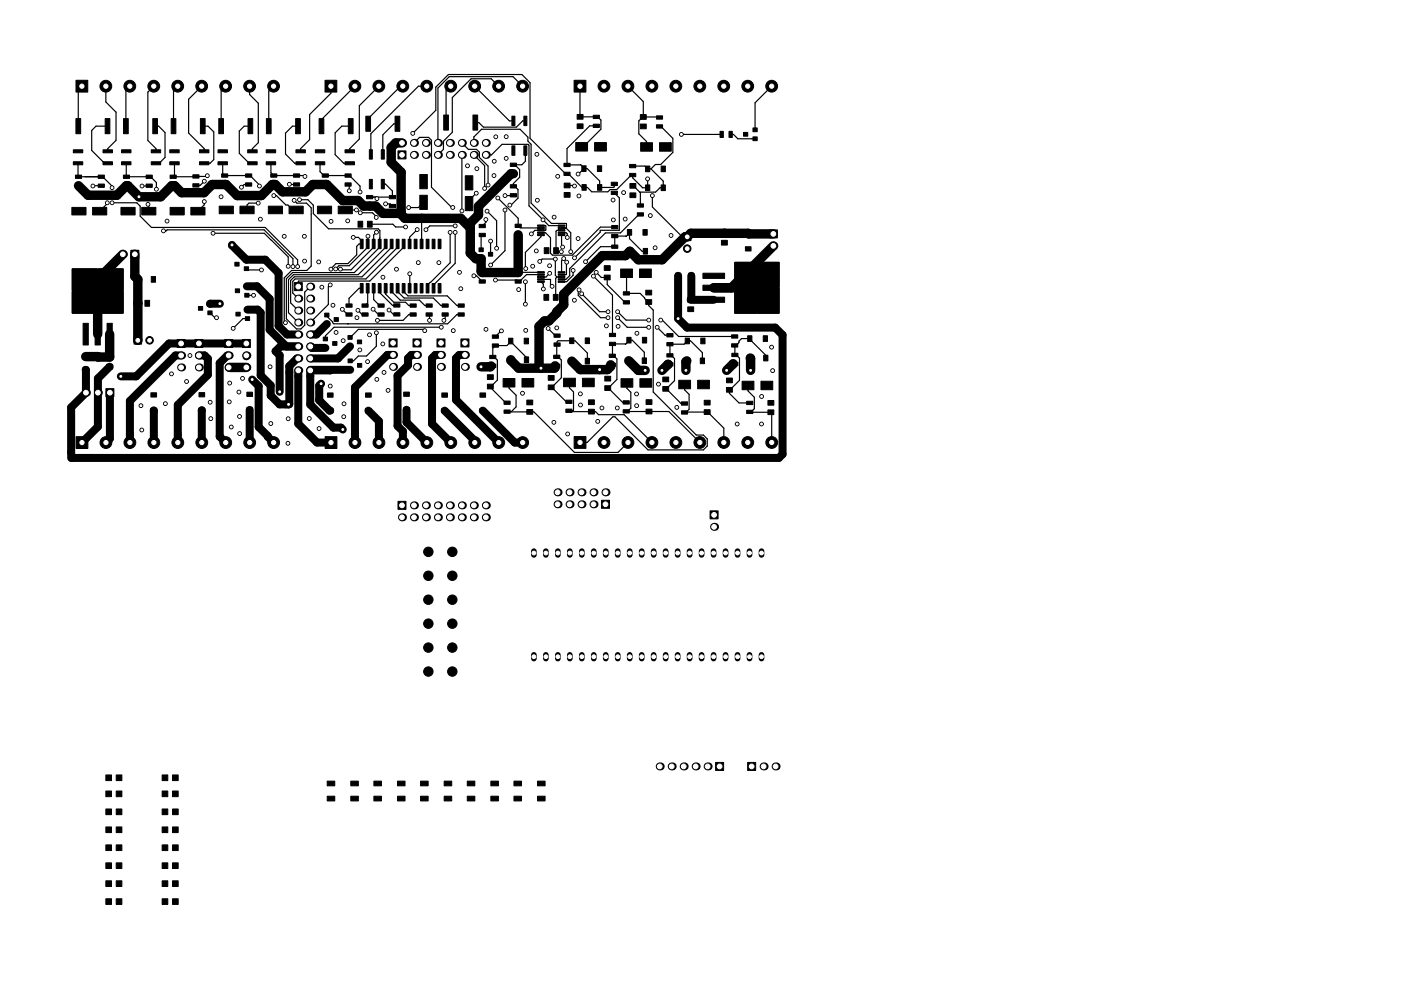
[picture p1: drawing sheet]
<svg xmlns="http://www.w3.org/2000/svg" width="297mm" height="210mm" viewBox="0 0 297 210" stroke-linecap="round" stroke-linejoin="round" font-family="sans-serif">
<g fill="none" stroke="#000" stroke-width="1.2">
<path d="M113.2 116.9v.8M115.7 116.9v.8M118.3 116.9v.8M120.8 116.9v.8M123.4 116.9v.8M125.9 116.9v.8M128.4 116.9v.8M131 116.9v.8M133.5 116.9v.8M136.1 116.9v.8M138.6 116.9v.8M141.1 116.9v.8"/>
<path d="M143.7 116.9v.8M146.2 116.9v.8M148.8 116.9v.8M151.3 116.9v.8M153.8 116.9v.8M156.4 116.9v.8M158.9 116.9v.8M161.5 116.9v.8M113.2 138.9v.8M115.7 138.9v.8M118.3 138.9v.8M120.8 138.9v.8"/>
<path d="M123.4 138.9v.8M125.9 138.9v.8M128.4 138.9v.8M131 138.9v.8M133.5 138.9v.8M136.1 138.9v.8M138.6 138.9v.8M141.1 138.9v.8M143.7 138.9v.8M146.2 138.9v.8M148.8 138.9v.8M151.3 138.9v.8"/>
<path d="M153.8 138.9v.8M156.4 138.9v.8M158.9 138.9v.8M161.5 138.9v.8"/>
</g>
<g fill="#000" stroke="#000" stroke-width=".21">
<path d="M16.1 17h2.5v2.5h-2.5zM68.9 17h2.5v2.5h-2.5zM121.7 17h2.5v2.5h-2.5zM16.1 25.2h1v3.2h-1zM16 37.2h1.3v.7h-1.3zM16 39.1h1.3v.7h-1.3zM15.5 34.3h2v.7h-2zM15.5 31.8h2v.6h-2zM20.8 39.1h1.3v.7h-1.3zM20.8 37.2h1.3v.7h-1.3zM22.3 25.2h1v3.2h-1zM21.8 31.8h2v.6h-2z"/>
<path d="M21.8 34.3h2v.7h-2zM26.2 25.2h1v3.2h-1zM26.2 39.1h1.3v.7h-1.3zM26.2 37.2h1.3v.7h-1.3zM25.8 34.3h2v.7h-2zM25.8 31.8h2v.6h-2zM31 37.2h1.3v.7h-1.3zM31 39.1h1.3v.7h-1.3zM32.4 25.2h1v3.2h-1zM32.1 31.8h2v.6h-2zM32.1 34.3h2v.7h-2zM36.3 25.2h1v3.2h-1z"/>
<path d="M36.1 39.1h1.3v.7h-1.3zM36.1 37.2h1.3v.7h-1.3zM36 31.8h2v.6h-2zM36 34.3h2v.7h-2zM40.9 39h1.3v.7h-1.3zM40.9 37.1h1.3v.7h-1.3zM42.5 25.2h1v3.2h-1zM42.3 34.3h2v.7h-2zM42.3 31.8h2v.6h-2zM46.4 25.2h1v3.2h-1zM46.2 31.8h2v.6h-2zM46.2 34.3h2v.7h-2z"/>
<path d="M47 38.8h1.3v.7h-1.3zM47 36.9h1.3v.7h-1.3zM52.1 36.9h1.3v.7h-1.3zM52.1 38.8h1.3v.7h-1.3zM52.6 25.2h1v3.2h-1zM52.5 34.3h2v.7h-2zM52.5 31.8h2v.6h-2zM56.5 25.2h1v3.2h-1zM56.4 31.8h2v.6h-2zM56.4 34.3h2v.7h-2zM57.4 36.9h1.3v.7h-1.3zM57.4 38.8h1.3v.7h-1.3z"/>
<path d="M62.2 38.8h1.3v.7h-1.3zM62.2 36.9h1.3v.7h-1.3zM62.7 25.2h1v3.2h-1zM62.7 34.3h2v.7h-2zM62.7 31.8h2v.6h-2zM67.7 25.2h1v3.2h-1zM66.9 34.3h2v.7h-2zM66.9 31.8h2v.6h-2zM68.3 38.8h1.3v.7h-1.3zM68.3 36.9h1.3v.7h-1.3zM73.1 36.9h1.3v.7h-1.3zM73.1 38.8h1.3v.7h-1.3z"/>
<path d="M73.9 25.2h1v3.2h-1zM73.2 31.8h2v.6h-2zM73.2 34.3h2v.7h-2zM78.3 38.1h.6v2h-.6zM78.3 31.8h.6v2h-.6zM77.6 24.7h1v3.2h-1zM80.8 38.1h.7v2h-.7zM80.8 31.8h.7v2h-.7zM83.8 24.7h1v3.2h-1zM84.4 32h1.7v1.7h-1.7zM89 37h1.6v3h-1.6zM94.1 24.4h1v3.2h-1z"/>
<path d="M98.7 37.3h1.6v3h-1.6zM100.3 24.4h1v3.2h-1zM108.2 39.2h1.3v.7h-1.3zM108.5 24.6h.7v2h-.7zM108.5 30.9h.7v2h-.7zM108.2 34.6h1.3v.7h-1.3zM108.2 36.5h1.3v.7h-1.3zM111.1 24.6h.6v2h-.6zM111.1 30.9h.6v2h-.6zM119.6 38.8h1.3v1h-1.3zM119.6 36.5h1.3v.7h-1.3zM119.6 34.6h1.3v.7h-1.3z"/>
<path d="M122.1 30.2h2.5v1.8h-2.5zM123.4 35.2h.9v1.2h-.9zM122.4 26.3h1.2v1h-1.2zM122.4 24.3h1.2v1h-1.2zM125.8 24.4h1.3v.7h-1.3zM125.8 26.3h1.3v.7h-1.3zM126.1 30.2h2.5v1.8h-2.5zM126.7 35.2h.9v1.2h-.9zM129.6 38.7h1.3v.7h-1.3zM133.6 38.9h1.2v1h-1.2zM133.5 34.9h1.3v.7h-1.3zM133.5 36.8h1.3v.7h-1.3z"/>
<path d="M135.8 30.3h2.5v1.8h-2.5zM136.9 35.2h.9v1.2h-.9zM135.8 24.3h1.2v1h-1.2zM135.8 26.3h1.2v1h-1.2zM139.2 26.5h1.3v.7h-1.3zM139.2 24.6h1.3v.7h-1.3zM139.8 30.3h2.5v1.8h-2.5zM140.2 35.2h.9v1.2h-.9zM152.7 27.9h.7v1.3h-.7zM154.6 27.9h.7v1.3h-.7zM157.6 28.1h.9v.8h-.9zM159.6 29h.9v.8h-.9z"/>
<path d="M159.6 27.1h.9v.8h-.9zM15.2 44h3v1.6h-3zM19.6 44h3v1.6h-3zM25.6 44h3v1.6h-3zM27.7 53.1h1.7v1.7h-1.7zM28.8 58.7h.9v1.2h-.9zM30 44h3v1.6h-3zM32.1 58.7h.9v1.2h-.9zM36.1 44h3v1.6h-3zM40.5 44h3v1.6h-3zM46.5 43.7h3v1.6h-3zM49.8 55.7h.9v.8h-.9z"/>
<path d="M50.9 43.7h3v1.6h-3zM51.8 56.6h.9v.8h-.9zM51.8 54.7h.9v.8h-.9zM56.9 43.7h3v1.6h-3zM61.3 43.7h3v1.6h-3zM67.3 43.7h3v1.6h-3zM71.7 43.7h3v1.6h-3zM75.9 46.9h1v1.3h-1zM76.4 50.8h.6v2h-.6zM77.7 50.8h.6v2h-.6zM77.9 46.9h1v1.3h-1zM77.7 41.5h1.3v.7h-1.3z"/>
<path d="M77.7 43.4h1.3v.7h-1.3zM78.9 50.8h.6v2h-.6zM80.2 50.8h.6v2h-.6zM81.5 50.8h.6v2h-.6zM82.5 43.4h1.3v.7h-1.3zM82.5 41.5h1.3v.7h-1.3zM82.7 50.8h.6v2h-.6zM84 50.8h.6v2h-.6zM85.3 50.8h.6v2h-.6zM86.5 50.8h.6v2h-.6zM87.8 50.8h.6v2h-.6zM89 41.4h1.6v3h-1.6z"/>
<path d="M89.1 50.8h.6v2h-.6zM90.4 50.8h.6v2h-.6zM91.6 50.8h.6v2h-.6zM92.9 50.8h.6v2h-.6zM98.7 41.7h1.6v3h-1.6zM101.6 54.5h.9v.8h-.9zM101.6 52.6h.9v.8h-.9zM101.6 59.4h1.3v.7h-1.3zM101.6 57.5h1.3v.7h-1.3zM101.6 49.5h1.3v.7h-1.3zM101.6 47.6h1.3v.7h-1.3zM103.6 53.5h.9v.8h-.9z"/>
<path d="M108.2 41.1h1.3v.7h-1.3zM109.2 57.5h1.3v.7h-1.3zM109.2 59.4h1.3v.7h-1.3zM109.2 47.6h1.3v.7h-1.3zM109.2 49.5h1.3v.7h-1.3zM114 49.7h1.4v.3h-1.4zM114 49.2h1.4v.3h-1.4zM114 48.7h1.4v.3h-1.4zM114 48.2h1.4v.3h-1.4zM114 47.7h1.4v.3h-1.4zM114 57.6h1.4v.3h-1.4zM114 58.1h1.4v.3h-1.4z"/>
<path d="M114 58.6h1.4v.3h-1.4zM114 59.1h1.4v.3h-1.4zM114 59.6h1.4v.3h-1.4zM115.4 52.6h1v1.2h-1zM118.4 47.7h1.4v.3h-1.4zM118.4 48.2h1.4v.3h-1.4zM118.4 48.7h1.4v.3h-1.4zM118.4 49.2h1.4v.3h-1.4zM118.4 49.7h1.4v.3h-1.4zM118.4 59.6h1.4v.3h-1.4zM118.4 59.1h1.4v.3h-1.4zM118.4 58.6h1.4v.3h-1.4z"/>
<path d="M118.4 58.1h1.4v.3h-1.4zM118.4 57.6h1.4v.3h-1.4zM117.4 52.6h1v1.2h-1zM119.6 40.8h1.3v1h-1.3zM123.4 39.2h.9v1.2h-.9zM126.7 39.2h.9v1.2h-.9zM128.1 58.4h1.3v1h-1.3zM128.1 56.4h1.3v1h-1.3zM129.6 40.6h1.3v.7h-1.3zM129.7 47.8h1.3v.7h-1.3zM129.7 49.7h1.3v.7h-1.3zM129.7 53.9h1.3v.7h-1.3z"/>
<path d="M129.7 52h1.3v.7h-1.3zM131.6 57.1h2.5v1.8h-2.5zM133 48.7h.9v1.2h-.9zM133.1 52.7h.9v1.2h-.9zM133.6 40.9h1.2v1h-1.2zM135.1 43.2h1.3v.7h-1.3zM135.1 45.1h1.3v.7h-1.3zM135.6 57.1h2.5v1.8h-2.5zM136.3 48.7h.9v1.2h-.9zM136.4 52.7h.9v1.2h-.9zM136.9 39.2h.9v1.2h-.9zM140.2 39.2h.9v1.2h-.9z"/>
<path d="M143.2 58h1.1v1.1h-1.1zM144.9 49.4h1.6v1.6h-1.6zM146 58h1.1v1.1h-1.1zM149 58h4.6v1.1h-4.6zM153 49h1.2v1h-1.2zM153 51h1.2v1h-1.2zM158 49.1h1.2v.9h-1.2zM158 52.4h1.2v.9h-1.2zM163.1 48.8h1.7v1.7h-1.7zM17.6 77.9h1.1v1.1h-1.1zM17.6 75.1h1.1v1.1h-1.1zM17.6 68.6h1.1v4.6h-1.1z"/>
<path d="M15.3 57h5.3v4.6h-5.3zM15.3 61.9h5.3v4.5h-5.3zM20.2 68.6h1.1v4.6h-1.1zM22.6 77.3h1.3v1h-1.3zM22.6 75.3h1.3v1h-1.3zM22.7 68.6h1.1v4.6h-1.1zM20.9 61.9h5.2v4.5h-5.2zM20.9 57h5.2v4.6h-5.2zM15.3 57h10.8v9.4h-10.8zM28.4 71.4h1.6v1.6h-1.6zM28.7 63.7h1v1.3h-1zM30.7 63.7h1v1.3h-1z"/>
<path d="M37.5 72h1.7v1.7h-1.7zM41.3 72h1.7v1.7h-1.7zM42.1 65h.9v.8h-.9zM44.1 66h.9v.8h-.9zM44.1 64.1h.9v.8h-.9zM47.6 72h1.7v1.7h-1.7zM49.9 61.3h.9v.8h-.9zM50 66.2h.9v.8h-.9zM51.4 72h1.7v1.7h-1.7zM51.9 62.2h.9v.8h-.9zM51.9 60.3h.9v.8h-.9zM52 65.3h.9v.8h-.9z"/>
<path d="M52 67.2h.9v.8h-.9zM62.4 60h1.7v1.7h-1.7zM68.5 71.5h.9v.8h-.9zM68.5 73.4h.9v.8h-.9zM68.8 66.4h.9v.8h-.9zM68.8 68.3h.9v.8h-.9zM70.5 72.5h.9v.8h-.9zM70.8 67.4h.9v.8h-.9zM73.8 73.1h.9v.8h-.9zM73.8 71.2h.9v.8h-.9zM73.8 78.1h.9v.8h-.9zM73.8 76.2h.9v.8h-.9z"/>
<path d="M73.4 64.5h1.3v.7h-1.3zM73.4 66.4h1.3v.7h-1.3zM75.8 72.1h.9v.8h-.9zM75.8 77.1h.9v.8h-.9zM76.4 60.2h.6v2h-.6zM76.7 64.5h1.3v.7h-1.3zM76.7 66.4h1.3v.7h-1.3zM77.7 60.2h.6v2h-.6zM78.9 60.2h.6v2h-.6zM80.2 60.2h.6v2h-.6zM80.1 66.4h1.3v.7h-1.3zM80.1 64.5h1.3v.7h-1.3z"/>
<path d="M81.5 60.2h.6v2h-.6zM82.5 71.9h1.7v1.7h-1.7zM82.7 60.2h.6v2h-.6zM84 60.2h.6v2h-.6zM83.5 66.4h1.3v.7h-1.3zM83.5 64.5h1.3v.7h-1.3zM85.3 60.2h.6v2h-.6zM86.5 60.2h.6v2h-.6zM87.6 71.9h1.7v1.7h-1.7zM86.9 66.4h1.3v.7h-1.3zM86.9 64.5h1.3v.7h-1.3zM87.8 60.2h.6v2h-.6z"/>
<path d="M89.1 60.2h.6v2h-.6zM90.4 60.2h.6v2h-.6zM90.3 64.5h1.3v.7h-1.3zM90.3 66.4h1.3v.7h-1.3zM91.6 60.2h.6v2h-.6zM92.6 71.9h1.7v1.7h-1.7zM92.9 60.2h.6v2h-.6zM93.7 66.4h1.3v.7h-1.3zM93.7 64.5h1.3v.7h-1.3zM97.7 71.9h1.7v1.7h-1.7zM97.1 64.5h1.3v.7h-1.3zM97.1 66.4h1.3v.7h-1.3z"/>
<path d="M103.8 75.4h1.3v.7h-1.3zM103.8 77.3h1.3v.7h-1.3zM104.4 73h1.3v.7h-1.3zM104.4 71.1h1.3v.7h-1.3zM107.8 71.8h.9v1.2h-.9zM107.9 75.7h.9v1.2h-.9zM111.1 71.8h.9v1.2h-.9zM111.2 75.7h.9v1.2h-.9zM115.3 62.5h1v1.2h-1zM117.3 62.5h1v1.2h-1zM117.4 77.3h1.3v.7h-1.3zM117.4 75.4h1.3v.7h-1.3z"/>
<path d="M117.5 70.9h1.3v.7h-1.3zM117.5 72.8h1.3v.7h-1.3zM120.8 76h.9v1.2h-.9zM120.8 71.7h.9v1.2h-.9zM124.1 76h.9v1.2h-.9zM124.1 71.7h.9v1.2h-.9zM129.2 77h1.3v.7h-1.3zM129.2 75.1h1.3v.7h-1.3zM129.2 72.6h1.3v.7h-1.3zM129.2 70.7h1.3v.7h-1.3zM132.2 63.8h1.3v.7h-1.3zM132.2 61.9h1.3v.7h-1.3z"/>
<path d="M132.9 75.9h.9v1.2h-.9zM132.9 71.6h.9v1.2h-.9zM136.2 75.9h.9v1.2h-.9zM136.2 71.6h.9v1.2h-.9zM136.9 61.6h1.3v1h-1.3zM136.9 63.6h1.3v1h-1.3zM141.4 70.8h1.3v.7h-1.3zM141.4 72.7h1.3v.7h-1.3zM141.4 75h1.3v.7h-1.3zM141.4 76.9h1.3v.7h-1.3zM145.2 76h.9v1.2h-.9zM145.3 71.7h.9v1.2h-.9z"/>
<path d="M145.8 63.1h1.3v1h-1.3zM145.8 65.1h1.3v1h-1.3zM148.5 76h.9v1.2h-.9zM148.6 71.7h.9v1.2h-.9zM149 60.5h4.6v1.1h-4.6zM149 63h4.6v1.1h-4.6zM155.8 55.7h9.4v10.8h-9.4zM155.8 55.7h4.5v5.2h-4.5zM155.8 61.2h4.5v5.3h-4.5zM155.1 71h1.3v.7h-1.3zM155.1 72.9h1.3v.7h-1.3zM155.2 75h1.3v.7h-1.3z"/>
<path d="M155.2 76.9h1.3v.7h-1.3zM158.5 71.2h.9v1.2h-.9zM158.6 75.4h.9v1.2h-.9zM160.6 61.2h4.6v5.3h-4.6zM160.6 55.7h4.6v5.2h-4.6zM161.8 71.2h.9v1.2h-.9zM161.9 75.4h.9v1.2h-.9zM16.1 92.6h2.5v2.5h-2.5zM22.4 82.5h1.7v1.7h-1.7zM32 86.6h1.2v.9h-1.2zM32 83.3h1.2v.9h-1.2zM42.2 83.3h1.2v.9h-1.2z"/>
<path d="M42.2 86.6h1.2v.9h-1.2zM52.3 86.5h1.2v.9h-1.2zM52.3 83.2h1.2v.9h-1.2zM68.9 92.6h2.5v2.5h-2.5zM69.4 83.4h1.2v.9h-1.2zM69.4 86.7h1.2v.9h-1.2zM77.5 83.4h1.2v.9h-1.2zM77.5 86.7h1.2v.9h-1.2zM85.6 86.5h1.2v.9h-1.2zM85.6 83.2h1.2v.9h-1.2zM93.7 83.4h1.2v.9h-1.2zM93.7 86.7h1.2v.9h-1.2z"/>
<path d="M101.8 86.7h1.2v.9h-1.2zM101.8 83.4h1.2v.9h-1.2zM103.3 79.5h1.3v1h-1.3zM103.3 81.5h1.3v1h-1.3zM106.7 80.3h2.5v1.8h-2.5zM106.9 87h1.3v.7h-1.3zM106.9 85.1h1.3v.7h-1.3zM110.7 80.3h2.5v1.8h-2.5zM111.7 84.9h1.2v1h-1.2zM111.7 86.9h1.2v1h-1.2zM116.2 79.7h1.3v1h-1.3zM116.2 81.7h1.3v1h-1.3z"/>
<path d="M119.5 80.2h2.5v1.8h-2.5zM120 86.8h1.3v.7h-1.3zM120 84.9h1.3v.7h-1.3zM121.7 92.6h2.5v2.5h-2.5zM123.5 80.2h2.5v1.8h-2.5zM124.8 86.8h1.2v1h-1.2zM124.8 84.8h1.2v1h-1.2zM128.2 81.8h1.3v1h-1.3zM128.2 79.8h1.3v1h-1.3zM131.7 80.3h2.5v1.8h-2.5zM132.1 86.9h1.3v.7h-1.3zM132.1 85h1.3v.7h-1.3z"/>
<path d="M135.7 80.3h2.5v1.8h-2.5zM137 84.8h1.2v1h-1.2zM137 86.8h1.2v1h-1.2zM140.5 82h1.3v1h-1.3zM140.5 80h1.3v1h-1.3zM143.9 80.7h2.5v1.8h-2.5zM144.5 85.3h1.3v.7h-1.3zM144.5 87.2h1.3v.7h-1.3zM147.9 80.7h2.5v1.8h-2.5zM149.3 84.9h1.3v1h-1.3zM149.3 86.9h1.3v1h-1.3zM154 80.2h1.3v1h-1.3z"/>
<path d="M154 82.2h1.3v1h-1.3zM157.3 80.9h2.5v1.8h-2.5zM158.3 87h1.3v.7h-1.3zM158.3 85.1h1.3v.7h-1.3zM161.3 80.9h2.5v1.8h-2.5zM162.8 87h1.3v1h-1.3zM162.8 85h1.3v1h-1.3zM84.4 106.4h1.7v1.7h-1.7zM127.5 106.1h1.7v1.7h-1.7zM150.6 108.4h1.6v1.7h-1.6zM22.4 179.3h1.2v1.2h-1.2zM22.4 175.4h1.2v1.2h-1.2z"/>
<path d="M22.4 171.6h1.2v1.2h-1.2zM22.4 167.8h1.2v1.2h-1.2zM22.4 164.4h1.2v1.2h-1.2zM24.6 179.3h1.2v1.2h-1.2zM24.6 175.4h1.2v1.2h-1.2zM24.6 171.6h1.2v1.2h-1.2zM24.6 167.8h1.2v1.2h-1.2zM24.6 164.4h1.2v1.2h-1.2zM34.4 179.3h1.2v1.2h-1.2zM34.4 175.4h1.2v1.2h-1.2zM34.4 171.6h1.2v1.2h-1.2zM34.4 167.8h1.2v1.2h-1.2z"/>
<path d="M34.4 164.4h1.2v1.2h-1.2zM36.6 179.3h1.2v1.2h-1.2zM36.6 175.4h1.2v1.2h-1.2zM36.6 171.6h1.2v1.2h-1.2zM36.6 167.8h1.2v1.2h-1.2zM36.6 164.4h1.2v1.2h-1.2zM69.4 168.9h1.6v1h-1.6zM69.4 165.7h1.6v1h-1.6zM74.4 168.9h1.6v1h-1.6zM74.4 165.7h1.6v1h-1.6zM79.3 165.7h1.6v1h-1.6zM79.3 168.9h1.6v1h-1.6z"/>
<path d="M84.3 165.7h1.6v1h-1.6zM84.3 168.9h1.6v1h-1.6zM89.2 165.7h1.6v1h-1.6zM89.2 168.9h1.6v1h-1.6zM94.2 165.7h1.6v1h-1.6zM94.2 168.9h1.6v1h-1.6zM99.1 165.7h1.6v1h-1.6zM99.1 168.9h1.6v1h-1.6zM104.1 165.7h1.6v1h-1.6zM104.1 168.9h1.6v1h-1.6zM109 168.9h1.6v1h-1.6zM109 165.7h1.6v1h-1.6z"/>
<path d="M114 168.9h1.6v1h-1.6zM114 165.7h1.6v1h-1.6zM151.7 161.8h1.7v1.7h-1.7zM158.5 161.8h1.7v1.7h-1.7zM22.4 190.7h1.2v1.2h-1.2zM22.4 183.1h1.2v1.2h-1.2zM22.4 186.9h1.2v1.2h-1.2zM24.6 190.7h1.2v1.2h-1.2zM24.6 183.1h1.2v1.2h-1.2zM24.6 186.9h1.2v1.2h-1.2zM34.4 190.7h1.2v1.2h-1.2zM34.4 183.1h1.2v1.2h-1.2z"/>
<path d="M34.4 186.9h1.2v1.2h-1.2zM36.6 190.7h1.2v1.2h-1.2zM36.6 183.1h1.2v1.2h-1.2zM36.6 186.9h1.2v1.2h-1.2z"/>
<circle cx="22.4" cy="18.3" r="1.25"/>
<circle cx="27.5" cy="18.3" r="1.25"/>
<circle cx="32.6" cy="18.3" r="1.25"/>
<circle cx="37.7" cy="18.3" r="1.25"/>
<circle cx="42.8" cy="18.3" r="1.25"/>
<circle cx="47.8" cy="18.3" r="1.25"/>
<circle cx="52.9" cy="18.3" r="1.25"/>
<circle cx="58" cy="18.3" r="1.25"/>
<circle cx="75.2" cy="18.3" r="1.25"/>
<circle cx="80.3" cy="18.3" r="1.25"/>
<circle cx="85.4" cy="18.3" r="1.25"/>
<circle cx="90.5" cy="18.3" r="1.25"/>
<circle cx="95.6" cy="18.3" r="1.25"/>
<circle cx="100.6" cy="18.3" r="1.25"/>
<circle cx="105.7" cy="18.3" r="1.25"/>
<circle cx="110.8" cy="18.3" r="1.25"/>
<circle cx="128.1" cy="18.3" r="1.25"/>
<circle cx="133.1" cy="18.3" r="1.25"/>
<circle cx="138.2" cy="18.3" r="1.25"/>
<circle cx="143.3" cy="18.3" r="1.25"/>
<circle cx="148.4" cy="18.3" r="1.25"/>
<circle cx="153.5" cy="18.3" r="1.25"/>
<circle cx="158.5" cy="18.3" r="1.25"/>
<circle cx="163.6" cy="18.3" r="1.25"/>
<circle cx="19.7" cy="39.5" r=".4"/>
<circle cx="23.8" cy="39.8" r=".4"/>
<circle cx="30.1" cy="39.5" r=".4"/>
<circle cx="43.3" cy="38.5" r=".4"/>
<circle cx="44" cy="37.3" r=".4"/>
<circle cx="51.2" cy="39.7" r=".4"/>
<circle cx="55" cy="39.5" r=".4"/>
<circle cx="61.4" cy="39.1" r=".4"/>
<circle cx="64.7" cy="37.4" r=".4"/>
<circle cx="87.5" cy="28.3" r=".4"/>
<circle cx="99.1" cy="35.2" r=".4"/>
<circle cx="101.1" cy="35.8" r=".4"/>
<circle cx="102.8" cy="40" r=".4"/>
<circle cx="103.5" cy="39.3" r=".4"/>
<circle cx="104.7" cy="37.3" r=".4"/>
<circle cx="104.8" cy="34.2" r=".4"/>
<circle cx="105.1" cy="29" r=".4"/>
<circle cx="107.3" cy="33.6" r=".4"/>
<circle cx="107.3" cy="29" r=".4"/>
<circle cx="113.8" cy="32.7" r=".4"/>
<circle cx="118.2" cy="37.4" r=".4"/>
<circle cx="121.8" cy="39.5" r=".4"/>
<circle cx="122.6" cy="36.9" r=".4"/>
<circle cx="137.3" cy="37.9" r=".4"/>
<circle cx="144.5" cy="28.5" r=".4"/>
<circle cx="22.7" cy="43" r=".4"/>
<circle cx="23.8" cy="43" r=".4"/>
<circle cx="29.5" cy="41.8" r=".4"/>
<circle cx="31.4" cy="43.4" r=".4"/>
<circle cx="33.2" cy="40.2" r=".4"/>
<circle cx="34.7" cy="49" r=".4"/>
<circle cx="35.4" cy="46.9" r=".4"/>
<circle cx="43.3" cy="42.8" r=".4"/>
<circle cx="45.2" cy="49.5" r=".4"/>
<circle cx="46.9" cy="41.8" r=".4"/>
<circle cx="49.2" cy="52" r=".4"/>
<circle cx="54.7" cy="43.1" r=".4"/>
<circle cx="55.2" cy="46.5" r=".4"/>
<circle cx="55.4" cy="57.3" r=".4"/>
<circle cx="58.1" cy="41.5" r=".4"/>
<circle cx="60.3" cy="50.1" r=".4"/>
<circle cx="61.1" cy="56.5" r=".4"/>
<circle cx="62.1" cy="56.6" r=".4"/>
<circle cx="62.4" cy="42.5" r=".4"/>
<circle cx="63.1" cy="56.6" r=".4"/>
<circle cx="63.5" cy="42.4" r=".4"/>
<circle cx="64.5" cy="50.1" r=".4"/>
<circle cx="64.6" cy="55.4" r=".4"/>
<circle cx="67.6" cy="55.6" r=".4"/>
<circle cx="70.2" cy="57.1" r=".4"/>
<circle cx="70.2" cy="47" r=".4"/>
<circle cx="71.2" cy="57.1" r=".4"/>
<circle cx="72.2" cy="57.1" r=".4"/>
<circle cx="73.7" cy="46.9" r=".4"/>
<circle cx="74.1" cy="40.5" r=".4"/>
<circle cx="74.9" cy="50.4" r=".4"/>
<circle cx="75.6" cy="44.5" r=".4"/>
<circle cx="76.3" cy="40.7" r=".4"/>
<circle cx="76.4" cy="45.1" r=".4"/>
<circle cx="78" cy="50.1" r=".4"/>
<circle cx="79.8" cy="46.1" r=".4"/>
<circle cx="79.8" cy="49.3" r=".4"/>
<circle cx="79.9" cy="42.1" r=".4"/>
<circle cx="81.2" cy="58.8" r=".4"/>
<circle cx="81.7" cy="43.3" r=".4"/>
<circle cx="84.1" cy="57.1" r=".4"/>
<circle cx="86" cy="48.2" r=".4"/>
<circle cx="86.6" cy="44" r=".4"/>
<circle cx="86.9" cy="58.1" r=".4"/>
<circle cx="88.5" cy="48.7" r=".4"/>
<circle cx="88.7" cy="55.7" r=".4"/>
<circle cx="90.3" cy="48.7" r=".4"/>
<circle cx="93.1" cy="55.7" r=".4"/>
<circle cx="95.4" cy="49.3" r=".4"/>
<circle cx="96" cy="44" r=".4"/>
<circle cx="96.5" cy="49.3" r=".4"/>
<circle cx="96.5" cy="47.9" r=".4"/>
<circle cx="97.4" cy="57.8" r=".4"/>
<circle cx="97.9" cy="44.7" r=".4"/>
<circle cx="100.5" cy="58.5" r=".4"/>
<circle cx="101" cy="41" r=".4"/>
<circle cx="103" cy="46.6" r=".4"/>
<circle cx="103.3" cy="44.8" r=".4"/>
<circle cx="104" cy="51.2" r=".4"/>
<circle cx="104" cy="56.2" r=".4"/>
<circle cx="105" cy="59.4" r=".4"/>
<circle cx="105.3" cy="52.7" r=".4"/>
<circle cx="105.5" cy="42" r=".4"/>
<circle cx="107.1" cy="44.6" r=".4"/>
<circle cx="107.1" cy="41.5" r=".4"/>
<circle cx="108.1" cy="43.5" r=".4"/>
<circle cx="111.4" cy="59.8" r=".4"/>
<circle cx="111.5" cy="57" r=".4"/>
<circle cx="112.7" cy="49.6" r=".4"/>
<circle cx="112.9" cy="56.5" r=".4"/>
<circle cx="113.7" cy="53.2" r=".4"/>
<circle cx="113.9" cy="42.5" r=".4"/>
<circle cx="114.4" cy="55.5" r=".4"/>
<circle cx="115.1" cy="46.6" r=".4"/>
<circle cx="116.5" cy="56.4" r=".4"/>
<circle cx="116.5" cy="58" r=".4"/>
<circle cx="117.5" cy="46.1" r=".4"/>
<circle cx="117.7" cy="55" r=".4"/>
<circle cx="119" cy="53.4" r=".4"/>
<circle cx="119.3" cy="52.4" r=".4"/>
<circle cx="119.5" cy="54.9" r=".4"/>
<circle cx="120.2" cy="55.6" r=".4"/>
<circle cx="120.3" cy="50.4" r=".4"/>
<circle cx="121" cy="53.4" r=".4"/>
<circle cx="121.5" cy="57.4" r=".4"/>
<circle cx="121.8" cy="54.7" r=".4"/>
<circle cx="122.6" cy="50.6" r=".4"/>
<circle cx="122.7" cy="41.6" r=".4"/>
<circle cx="124.1" cy="55.5" r=".4"/>
<circle cx="125.8" cy="58.6" r=".4"/>
<circle cx="126.4" cy="57.8" r=".4"/>
<circle cx="130" cy="42.4" r=".4"/>
<circle cx="130" cy="46.7" r=".4"/>
<circle cx="132.2" cy="40.9" r=".4"/>
<circle cx="132.5" cy="46.5" r=".4"/>
<circle cx="137.9" cy="45.7" r=".4"/>
<circle cx="138.3" cy="41.5" r=".4"/>
<circle cx="138.9" cy="52.6" r=".4"/>
<circle cx="142.3" cy="50" r=".4"/>
<circle cx="145.7" cy="52.7" r=".8"/>
<circle cx="25.6" cy="79.9" r=".4"/>
<circle cx="31.7" cy="72.2" r=".8"/>
<circle cx="36.4" cy="79.3" r=".4"/>
<circle cx="40.3" cy="75.4" r=".4"/>
<circle cx="45.9" cy="67.4" r=".4"/>
<circle cx="46.6" cy="64.4" r=".4"/>
<circle cx="49.4" cy="69.7" r=".4"/>
<circle cx="53.8" cy="62.7" r=".4"/>
<circle cx="57.3" cy="77.8" r=".4"/>
<circle cx="60.5" cy="68.5" r=".4"/>
<circle cx="68.2" cy="60.9" r=".4"/>
<circle cx="70" cy="60.4" r=".4"/>
<circle cx="70.6" cy="64.8" r=".4"/>
<circle cx="71.3" cy="70.5" r=".4"/>
<circle cx="72.6" cy="65.6" r=".4"/>
<circle cx="72.8" cy="72.3" r=".4"/>
<circle cx="75.7" cy="67.4" r=".4"/>
<circle cx="75.9" cy="65.8" r=".4"/>
<circle cx="76.3" cy="74.2" r=".4"/>
<circle cx="77.9" cy="76.7" r=".4"/>
<circle cx="78.3" cy="71" r=".4"/>
<circle cx="79.1" cy="65.6" r=".4"/>
<circle cx="79.8" cy="70.6" r=".4"/>
<circle cx="80" cy="68" r=".4"/>
<circle cx="81.2" cy="73" r=".4"/>
<circle cx="81.4" cy="79" r=".4"/>
<circle cx="82.5" cy="65.8" r=".4"/>
<circle cx="90.1" cy="70.2" r=".4"/>
<circle cx="91.1" cy="68" r=".4"/>
<circle cx="93.6" cy="69.4" r=".4"/>
<circle cx="94.1" cy="68" r=".4"/>
<circle cx="96.1" cy="70.1" r=".4"/>
<circle cx="97.7" cy="61.3" r=".4"/>
<circle cx="102" cy="77.8" r=".4"/>
<circle cx="103" cy="69.9" r=".4"/>
<circle cx="106.3" cy="70.2" r=".4"/>
<circle cx="110" cy="61.4" r=".4"/>
<circle cx="111.4" cy="64.5" r=".4"/>
<circle cx="111.5" cy="70.1" r=".4"/>
<circle cx="114.7" cy="78.1" r=".4"/>
<circle cx="115.2" cy="61.3" r=".4"/>
<circle cx="116.2" cy="69.7" r=".4"/>
<circle cx="117.1" cy="60.8" r=".4"/>
<circle cx="118" cy="69.6" r=".4"/>
<circle cx="121.8" cy="63.7" r=".4"/>
<circle cx="122.8" cy="61.5" r=".4"/>
<circle cx="123.3" cy="62.3" r=".4"/>
<circle cx="127.1" cy="78.4" r=".4"/>
<circle cx="128.6" cy="69.1" r=".4"/>
<circle cx="128.9" cy="67.4" r=".4"/>
<circle cx="128.9" cy="66.1" r=".4"/>
<circle cx="130.9" cy="66.1" r=".4"/>
<circle cx="130.9" cy="67.4" r=".4"/>
<circle cx="131" cy="69.2" r=".4"/>
<circle cx="135" cy="70.7" r=".4"/>
<circle cx="136.8" cy="78.6" r=".4"/>
<circle cx="137.6" cy="69.4" r=".4"/>
<circle cx="137.6" cy="67.9" r=".4"/>
<circle cx="139.3" cy="69.4" r=".4"/>
<circle cx="140.1" cy="67.9" r=".4"/>
<circle cx="140.3" cy="78.6" r=".4"/>
<circle cx="143.8" cy="67.6" r=".4"/>
<circle cx="145.4" cy="78.6" r=".4"/>
<circle cx="154.1" cy="78.6" r=".4"/>
<circle cx="159.1" cy="78.6" r=".4"/>
<circle cx="163.6" cy="73.7" r=".4"/>
<circle cx="163.8" cy="78.6" r=".4"/>
<circle cx="22.5" cy="93.9" r="1.25"/>
<circle cx="27.5" cy="93.9" r="1.25"/>
<circle cx="29.9" cy="86.1" r=".4"/>
<circle cx="30.1" cy="91.2" r=".4"/>
<circle cx="32.6" cy="93.9" r="1.25"/>
<circle cx="35.1" cy="85.6" r=".4"/>
<circle cx="37.7" cy="93.9" r="1.25"/>
<circle cx="39.6" cy="80.9" r=".4"/>
<circle cx="42.8" cy="93.9" r="1.25"/>
<circle cx="44.6" cy="85.3" r=".4"/>
<circle cx="44.7" cy="88.8" r=".4"/>
<circle cx="47.9" cy="93.9" r="1.25"/>
<circle cx="48.6" cy="85.3" r=".4"/>
<circle cx="48.7" cy="81.3" r=".4"/>
<circle cx="49" cy="90.6" r=".4"/>
<circle cx="50.7" cy="83.2" r=".4"/>
<circle cx="50.8" cy="88.4" r=".4"/>
<circle cx="50.8" cy="92" r=".4"/>
<circle cx="51.4" cy="80.3" r=".4"/>
<circle cx="52.9" cy="93.9" r="1.25"/>
<circle cx="53.5" cy="80.5" r=".4"/>
<circle cx="57.4" cy="89.9" r=".4"/>
<circle cx="58" cy="93.9" r="1.25"/>
<circle cx="59.3" cy="83.1" r=".4"/>
<circle cx="61" cy="94.1" r=".4"/>
<circle cx="61.1" cy="88.8" r=".4"/>
<circle cx="61.2" cy="85.8" r=".4"/>
<circle cx="65.6" cy="88.8" r=".4"/>
<circle cx="67.7" cy="90.9" r=".4"/>
<circle cx="68.1" cy="81.4" r=".4"/>
<circle cx="70" cy="81.9" r=".4"/>
<circle cx="72.7" cy="91.1" r=".4"/>
<circle cx="72.9" cy="88.4" r=".4"/>
<circle cx="72.9" cy="85.7" r=".4"/>
<circle cx="75.3" cy="93.9" r="1.25"/>
<circle cx="79.9" cy="80.5" r=".4"/>
<circle cx="80.3" cy="93.9" r="1.25"/>
<circle cx="82.3" cy="82.8" r=".4"/>
<circle cx="85.4" cy="93.9" r="1.25"/>
<circle cx="90.5" cy="93.9" r="1.25"/>
<circle cx="95.6" cy="93.9" r="1.25"/>
<circle cx="100.7" cy="93.9" r="1.25"/>
<circle cx="105.7" cy="93.9" r="1.25"/>
<circle cx="110.8" cy="83.4" r=".4"/>
<circle cx="110.8" cy="93.9" r="1.25"/>
<circle cx="117.4" cy="89.6" r=".4"/>
<circle cx="120.4" cy="92.1" r=".4"/>
<circle cx="123" cy="83.6" r=".4"/>
<circle cx="123.1" cy="85.9" r=".4"/>
<circle cx="126.7" cy="89.4" r=".4"/>
<circle cx="127.6" cy="86.6" r=".4"/>
<circle cx="128.1" cy="93.9" r="1.25"/>
<circle cx="130.9" cy="86.6" r=".4"/>
<circle cx="133.1" cy="93.9" r="1.25"/>
<circle cx="135" cy="83.6" r=".4"/>
<circle cx="135" cy="86.1" r=".4"/>
<circle cx="138.2" cy="93.9" r="1.25"/>
<circle cx="139.6" cy="81.5" r=".4"/>
<circle cx="143.3" cy="93.9" r="1.25"/>
<circle cx="143.5" cy="86.4" r=".4"/>
<circle cx="148.4" cy="93.9" r="1.25"/>
<circle cx="153.5" cy="93.9" r="1.25"/>
<circle cx="156.3" cy="90" r=".4"/>
<circle cx="158.5" cy="93.9" r="1.25"/>
<circle cx="161.5" cy="90" r=".4"/>
<circle cx="161.5" cy="84.1" r=".4"/>
<circle cx="163.6" cy="93.9" r="1.25"/>
<circle cx="90.8" cy="117.1" r="1"/>
<circle cx="95.9" cy="117.1" r="1"/>
<circle cx="90.8" cy="132.3" r="1"/>
<circle cx="90.8" cy="137.4" r="1"/>
<circle cx="90.8" cy="127.2" r="1"/>
<circle cx="90.8" cy="122.2" r="1"/>
<circle cx="95.9" cy="132.3" r="1"/>
<circle cx="95.9" cy="137.4" r="1"/>
<circle cx="95.9" cy="127.2" r="1"/>
<circle cx="95.9" cy="122.2" r="1"/>
<circle cx="90.8" cy="142.5" r="1"/>
<circle cx="95.9" cy="142.5" r="1"/>
</g>
<g fill="#000">
<circle cx="85.2" cy="30.3" r=".85"/>
<circle cx="87.8" cy="30.3" r=".85"/>
<circle cx="87.8" cy="32.9" r=".85"/>
<circle cx="90.3" cy="30.3" r=".85"/>
<circle cx="90.3" cy="32.9" r=".85"/>
<circle cx="92.8" cy="30.3" r=".85"/>
<circle cx="92.8" cy="32.9" r=".85"/>
<circle cx="95.4" cy="32.9" r=".85"/>
<circle cx="95.4" cy="30.3" r=".85"/>
<circle cx="97.9" cy="32.9" r=".85"/>
<circle cx="97.9" cy="30.3" r=".85"/>
<circle cx="100.5" cy="32.9" r=".85"/>
<circle cx="100.5" cy="30.3" r=".85"/>
<circle cx="103" cy="30.3" r=".85"/>
<circle cx="103" cy="32.9" r=".85"/>
<circle cx="26" cy="53.9" r=".85"/>
<circle cx="164" cy="52.2" r=".85"/>
<circle cx="38.4" cy="75.4" r=".85"/>
<circle cx="38.4" cy="78" r=".85"/>
<circle cx="42.2" cy="75.4" r=".85"/>
<circle cx="42.2" cy="78" r=".85"/>
<circle cx="48.5" cy="75.4" r=".85"/>
<circle cx="48.5" cy="78" r=".85"/>
<circle cx="52.2" cy="75.4" r=".85"/>
<circle cx="52.2" cy="78" r=".85"/>
<circle cx="63.2" cy="71" r=".85"/>
<circle cx="63.2" cy="65.9" r=".85"/>
<circle cx="63.2" cy="68.4" r=".85"/>
<circle cx="63.2" cy="73.5" r=".85"/>
<circle cx="63.2" cy="78.6" r=".85"/>
<circle cx="63.2" cy="76" r=".85"/>
<circle cx="63.2" cy="63.3" r=".85"/>
<circle cx="65.8" cy="71" r=".85"/>
<circle cx="65.8" cy="73.5" r=".85"/>
<circle cx="65.8" cy="60.8" r=".85"/>
<circle cx="65.8" cy="63.3" r=".85"/>
<circle cx="65.8" cy="68.4" r=".85"/>
<circle cx="65.8" cy="78.6" r=".85"/>
<circle cx="65.8" cy="65.9" r=".85"/>
<circle cx="65.8" cy="76" r=".85"/>
<circle cx="83.3" cy="75.3" r=".85"/>
<circle cx="83.3" cy="77.8" r=".85"/>
<circle cx="88.4" cy="75.3" r=".85"/>
<circle cx="88.4" cy="77.8" r=".85"/>
<circle cx="93.5" cy="77.8" r=".85"/>
<circle cx="93.5" cy="75.3" r=".85"/>
<circle cx="98.6" cy="77.8" r=".85"/>
<circle cx="98.6" cy="75.3" r=".85"/>
<circle cx="18.2" cy="83.3" r=".85"/>
<circle cx="20.8" cy="83.3" r=".85"/>
<circle cx="85.2" cy="109.8" r=".85"/>
<circle cx="87.8" cy="109.8" r=".85"/>
<circle cx="87.8" cy="107.2" r=".85"/>
<circle cx="90.3" cy="109.8" r=".85"/>
<circle cx="90.3" cy="107.2" r=".85"/>
<circle cx="92.8" cy="109.8" r=".85"/>
<circle cx="92.8" cy="107.2" r=".85"/>
<circle cx="95.4" cy="109.8" r=".85"/>
<circle cx="95.4" cy="107.2" r=".85"/>
<circle cx="97.9" cy="109.8" r=".85"/>
<circle cx="97.9" cy="107.2" r=".85"/>
<circle cx="100.5" cy="107.2" r=".85"/>
<circle cx="100.5" cy="109.8" r=".85"/>
<circle cx="103" cy="109.8" r=".85"/>
<circle cx="103" cy="107.2" r=".85"/>
<circle cx="118.2" cy="107" r=".85"/>
<circle cx="118.2" cy="104.5" r=".85"/>
<circle cx="120.8" cy="104.5" r=".85"/>
<circle cx="120.8" cy="107" r=".85"/>
<circle cx="123.3" cy="104.5" r=".85"/>
<circle cx="123.3" cy="107" r=".85"/>
<circle cx="125.8" cy="107" r=".85"/>
<circle cx="125.8" cy="104.5" r=".85"/>
<circle cx="128.4" cy="104.5" r=".85"/>
<circle cx="151.4" cy="111.8" r=".85"/>
<circle cx="139.9" cy="162.6" r=".85"/>
<circle cx="142.4" cy="162.6" r=".85"/>
<circle cx="145" cy="162.6" r=".85"/>
<circle cx="147.5" cy="162.6" r=".85"/>
<circle cx="150" cy="162.6" r=".85"/>
<circle cx="161.9" cy="162.6" r=".85"/>
<circle cx="164.4" cy="162.6" r=".85"/>
</g>
<g fill="none" stroke="#000" stroke-width="2">
<path d="M16.6 39.4l2.1 2h6.1l2-2h.3l2.4 2.4h4.6l2.3-2.4h.6l1.5 1.5h4.7l1.8-1.8h2.9l2.4 2.4h5.1l2.3-2.4h.6l1.6 1.6h4.9l1.5-1.6h3l3.4 3.4h3.2l1.2 1.2h2.5l1.6 1.6h3.6M85.2 30.3h-1.3l-1 1v3.1l2.1 2.1v8.5l-.2 .3M108.8 36.9h-.4l-6.9 6.9v1.8l-1.8 1.7v6.4l1.2 1.2h1.1v2.7l.2 .2h7.7v-8M23.2 59.3l-2.5 2.4M26 53.9l-5.3 5.4v11.6M28.6 53.9v4.7l.6 .7v12.9M84.8 45.3l1.1 1h11.8l2 2.1M153.6 49.5h.1M164 49.6l-17.5-.1-.8 .7h-.5l-4.8 4.9h-5.1l-1.8-1.8-.9 .9h-4.9l-8.2 8.2v2.3l-1.4 1.4v.3l-1.7 1.7h-1l-1.1 1.1v8.5l.4 .4M164 52.2l-8.9 8.9M23.3 70.9v4.9l-5.1-.1M29.2 64.3h.1"/>
<path d="M29.2 72.2h.1M48.6 78h3.6M104.1 77.6l-.2 .2h-1.9M108.3 76.3l1.7 1.8h7.5l.2-.5M121.2 76.6l1.8 1.8h5.8l.7-.7v-.3M133.3 76.5l2.1 2.1h1.4M141.7 77.3l-1.4 1.3M145.6 76.6l-.2 .2v1.8M151.3 61.1h9.2M155.5 77.2l-1.4 1.4M159.1 76v2.6M162.9 63.8l.1 .1"/>
</g>
<g fill="none" stroke="#000" stroke-width=".25">
<path d="M17.4 18.3l-.8 .8v7.7M22.4 18.3v3.3l2.2 2.2v6l-1.8 1.7v.6M27.5 18.3l-.8 .8v7.7M32.6 18.3l-1.3 1.2v10.3l1.8 1.7v.6M37.7 18.3l-.9 .9v7.6M42.8 18.3l-2.8 2.8v7.1l3.3 3.3v.6M47.8 18.3l-.9 .9v7.6M52.9 18.3v1.8l1.9 1.8v8.4l-1.3 1.2v.6M58 18.3l-1 1v7.5M70.2 18.3v1.5l-4.6 4.5v5.3l-1.9 1.9v.6M75.2 18.3l-7 7.1v1.4M80.3 18.3l-4.1 4.1v7.1l-2 2v.6"/>
<path d="M85.4 18.3h-.5l-6.8 6.9v1.1M90.5 18.3h-1.8l-10.1 10.1v4.4M95.6 18.3l-1 1v6.7M100.6 18.3l7.4 7.3h.8M105.7 18.3l-1.6-1.6h-4.2l-4 4v7.4l-1.9 1.8v1.8l-1.2 1.2M110.8 18.3l-2-2h-13.5l-2.5 2.4v11.6M123 18.3v6.5h3.7l.7 .7v1.9l-3.7 3.7h-.4M133.1 18.3l3.3 3.2v3.3M163.6 18.3l-3.5 3.5v5.7M16.5 34.6l.1 2.9h5.2l2 2v.3M21.5 39.4l-1.8 .1M22.8 26.8h-2.4l-1 .9v4.2l2.8 2.7h.6"/>
<path d="M26.8 34.6v2.9h5.1l1.3 1.2v1.5M31.6 39.4l-1.5 .1M32.9 26.8h.7l1.4 1.3v5.3l-1.3 1.2h-.6M37 34.6v2.6l-.3 .3 7.1-.1 .2-.1M43 26.8h1.1l1.2 1.2v5.9l-.8 .7h-1.2M43.3 38.5l-.9 .8h-.9M47.2 34.6v2.2l.4 .4h5.4l2 2v.3M52.7 39.1h-.9l-.6 .6M53.1 26.8h-1.3l-1.1 1v4.7l2.1 2.1h.7M57.4 34.6v2l.6 .6h6.5l.2 .2M61.4 39.1h1.5M63.2 26.8h-1.2l-1.5 1.4v4.5l2 1.9h1.2"/>
<path d="M67.9 34.6v1.8l.8 .8h5.4l2.2 2.3v1.2M73.8 39.1l.3 .3v1.1M74.4 26.8h-1.9l-1.4 1.4v4.6l1.8 1.8h1.3M81.2 39.1h.5l1.5 1.4v1.3h-4.8M84.3 26.3h-.8l-2.3 2.3v4.2M87.5 28.3l4.9-4.9v-4.9l2.7-2.7h15.6l1.7 1.7v11.8l7.5 7.6h.6l2.9 2.9h1.1l1 .9h3.4l.5-.5h1.4l3-3.1h.3v.6l2.1 2.1h1.1v-1.9M87.8 30.3l1.1-1.2h2l.6 .7v9.9l4.3 4.3h.2M97.9 32.9v11.8M97.9 30.3l1.4 1.4h1.7l.6 .6v1.1l1.9 1.8v4.1M100.5 30.3v-1.2l1.6-1.7h8.2l1.6 1.7v.8l.7 .7v12.5l4.3 4.3h3.1v1M100.5 32.9l2.3 2.2v4.9M103 32.9h1.2l2.2-2.3h5.6l.2 .2v12.9l4.2 4.2h2.7"/>
<path d="M109.1 35l1.1 1v1.6l-1.4 1.3v.6h.3l.7 .7v1.8l-1.5 1.5h-.2M111.4 31.9v2.3l-.8 .8h-1.8M111.4 25.6h-.6l-1.3 1.4h-7l-1-1h-.7M120.2 39.3h1.5l.1 .2M123.8 35.8h.7l2.6 2.6v1.4h3l.1-.2v-.6M123.8 35.8l-1.2 1.1M126.4 24.8h.1M126.4 26.7h-1.4l-4.8 4.8v3.5l2.9-.1 .7 .9M134.1 35.2h2.6l.6 .6h.7M134.2 39.4l1.6 1.5v2.7M138 35.8l2.6 2.6v1.4h-.7l-.9 1h-3.4M139.8 26.8h.3l2.6 2.6v2.9l-2.6 2.6h-1.2l-.9 .9"/>
<path d="M139.8 24.9l-.1-.1h-3.4l-.9 .8v2.8l1.7 1.6v1.2M144.5 28.5h8.5M154.9 28.5h.6l.9 .9h3.7M22.7 43v.2l-1.6 1.6h-.7M23.8 43h5.2l.7 .7v2.2l2.4 2.4h24.1l6.9 6.8v1.5M31.4 43.4l.1 .1v1.3M34.7 49h.5l.2-.2h20.6l6.1 6.1v1.7M43.3 42.8v.6l-1.3 1.4M45.2 49.5h10.8l5.1 5v2M52.2 57l.3 .3h2.9M54.7 43.1h-1.9l-.4 .4v1M58 41.5h.6l2 2h.4l1.1 1h.7"/>
<path d="M62.4 42.5l.6 .6h2l1 1v12.4l-.9 .9h-3.3l-1.5 1.6v9.2l.2 .3M63.5 42.4h1.8l1.1 1.1v1.8l3.3 3.2h10.5l.3 .4v3.6l-5.4 5.3h-13.1l-1.3 1.3v8.5l2.2 2.2h.9l.8-.8v-7l1.2-1.2M73.2 44.5h2.4M74.9 50.4h1.1l.7 .7v1.4M76.4 45.1h2.6l.8 .9v.1M76.7 51.8h-.6l-.5 .5v1.8l-1.8 1.8h-2.6l-1 1.2M78 51.1v1.4l-4 3.9h-2.2l-.6 .7M78 50.1v1.7M78.4 47.6h4.9l.6 .6h2.1M79.6 41.8l.3 .3M79.8 49.3l-.6 .6v2.6l-4.8 4.7h-2.1l-.1-.1M81.2 45.3v.8"/>
<path d="M81.7 43.3h1l.5 .4h-.6M81.8 51.8v.7l-5.9 5.8h-13.7l-1 1v7.1l2 2M83 51.8v.7l-6.2 6.2h-14.4l-.8 .8v4.8l1.6 1.6M84.3 51.8v.7l-6.7 6.7h-15l-.5 .5v2.5l1.1 1.1M85.6 51.8v.7l-7.2 7.1h-15.1l-.1 1.2M86.9 58.1l-.1 3.1M88.5 48.7l-1.7 1.6v1.5M89.4 46.3v5.5M89.8 42.9l-1.1 1.1h-2.1M95.4 49.3v6.5l-4.7 4.7v.7M96.5 47.9h-5.4l-.8 .8M96.5 49.3v6.6l-4.6 4.6v.7"/>
<path d="M97.9 44.7h.1M100.5 58.5h.5l1.2 1.2M101 41l-1.5 1.5v.7M101 41h.1M102.2 49.9l-.2 .2v2.9M103 46.6v.6l-.8 .8M103.3 44.8l2 2v5.9M104 51.2v2.7M105.5 42l4.4 4.3v1.6l.4 .5h4.4M107.1 44.6v8.6l-3.1 3M109.1 41.4l-2 .1M111.4 59.8v4.7"/>
<path d="M114.4 55.5l.5-.5h2.8v3.4l.4 .4M114.7 57.8h-4.8M114.7 47.9h.9l.1 .9-2.3 .1-.7 .7M114.7 49.9v.3l-3.3 3.3 .1 3.5M114.7 59.3h2v1.1l.4 .4M114.7 58.3h-3.1l-1.4 1.4h-.3l-.3-.3h-4.6M114.7 59.8l.5 .5v1M116.5 58l-.7 .8h-1.1M118.1 58.8h1M118.1 58.8l-.3 .3v4M119.1 48.9h-1l-.2 .2v4.1l.2 .2h.9M119.1 48.4h.9"/>
<path d="M119.1 49.9v2.3l.2 .2M119.1 49.4h.9l.3 .2v.8M119.5 54.9l-.4 .4v2.5M120 48.4l1 1v4M120.2 55.6l-.1 2.6-1 .1M121.5 57.4v1l-1.4 1.4h-1M125.8 58.6l4.1 4v8.5M126.4 57.8l1.1 1.1h1.2v1.5l3.8 3.7h.3M130.2 40.9l1.1 1.1v6.8l-4 .1v.4l-5.5 5.4M130.3 48.2h-3l-5.9 5.9h-4.3l-.4-.4v-3.3l-1-1h-1M132.8 58v4.2M133.5 49.3v1.3l2.6 2.7h.7"/>
<path d="M133.5 49.4l-.7 .7h-2.5v2.2h-3l-3.2 3.2M135.8 45.5h-.3l-3.9 3.9h-3.2l-7.6 7.6v1.5l-.8 .8h-.9M138.3 41.5v2.4l6.4 6.3h1M44.5 66.4l1.1 1h.3M52.3 62.6l.1 .1M52.4 62.7h1.4M52.5 67.6h-1l-2.1 2.1M70 60.4l-.4 .4v3.8l-3.8 3.8M72.6 65.6l1.1 1.1h.3M75.9 65.8l.9 .9h.6M76.7 61.2h-.6l-2.1 2.1v1.5M78 61.2v3.1l-.6 .5"/>
<path d="M79.1 65.6l1.1 1.1h.6M79.2 61.2v2.4l1.3 1.2h.3M79.8 70.6v2.9l-2.1 2h-1.7l-1 1.1h-.8M80.5 61.2v.9l2.7 2.7h.9M81.8 61.2v1.2l1.7 1.7h2.5l.7 .7h.9M82.5 65.8l.9 .9h.7M83 61.2v.7l1.9 1.8h4l1.2 1.1h.9M84.3 61.2v.7l1.4 1.3h6.2l1.6 1.6h.9M85.6 61.2v.7l.9 .9h8.3l2.1 2h.9M87.6 66.7h-.9l-1.3 1.3h-5.4M90.1 70.2l-.3-.3h-13.8l-1.8 1.7M91 66.7l.1 1.3"/>
<path d="M93.6 69.4h-22.8l-1.8 1.9v.6M94.4 66.7v1l-.3 .3M97.8 66.7h-.9l-2 2h-24.1l-1.5-1.6v-.3M106.3 70.2l-1.3 1.2M108.3 72.5l3.3 3.3v.5M108.3 72.5l-.8 .8h-2.5l-.5 .6v1.8h.3l.7 .7v4.2l-1.5 1.4v.2l3.2 3.2h.3M108.3 72.4v.1M116.2 69.7l1.5 1.5h.4M122.8 61.5l-.2 .2v1l4.7 4.7h1.6M123.3 62.3l3.8 3.8h1.8M124.5 76.6v-1.7l-2.6-2.6h-3.6l-.2 .2-.1 .7v2.5h.3l.7 .7v3.7l-2 2.1M130.9 67.4l2.1 2h4.6"/>
<path d="M130.9 66.1l1.8 1.8h4.9M132.8 62.2h2.9l1.8 1.9v.7l1 1v17.4l9.1 9.1h1.5l.9 .8v1.5l-.9 .9h-11.7l-7-7.1h-.5l-5.4 5.5h-1.5M132.8 62.2h.1M136.6 76.5v-1.8l-2.5-2.5h-.8l-.7 .8h-2.7l-.1 2.5h.3l.7 .7v4.3l-1.8 1.8M139.3 69.4l1.7 1.7h1M140.1 67.9h.3l3.5 3.5h11.9M148.9 76.6v-1.8l-2.5-2.5h-.7l-.7 .7h-3v2.4h.3l.7 .7v4.7l-1.7 1.7M151.3 63.6h.1M162.4 76v-.6l-3.4-3.6h-1.8l-.5 .6v.3l-.6 .6h-.3v2h.3l.7 .7v4.7l-2.2 2v.8l2.1 2h2.3M107.9 81.2v1.2l1.5 1.5v2.4l-1 1h-.9l5.7 .1 8.6 8.6h9.2l2.1-2.1M116.9 82.2h.1M117 82.2l3.1 3h.5"/>
<path d="M120.7 81.1v1.2l.9 .9v3.9h-1l.2 .2h5.5l.6 .7h5.4l5.9 5.9M128.8 82.3h.2M129 82.3l3 3.1h.8M132.8 87.3h9l6.6 6.6M132.8 87.3h.1M132.9 81.2v1.2l.8 .8v3.4l-.6 .7M141.2 82.5h.1M141.3 82.5l3.1 3.1h.7M145.2 81.6v1.1l.9 1v3.1l-.7 .7h-.3l5-.1 3.4 3.4v3.1M158.6 81.8v1.1l1.3 1.4v2.4l-.6 .7h-.3l4.4 .1 .2 .1v6.3"/>
</g>
<g fill="none" stroke="#000" stroke-width="1.7">
<path d="M49.2 52l3 3.1h4l2.9 2.8v11.3l1.8 1.8h2.3M143.8 58.5v9.1l1.9 1.9h18.7l1.5 1.6v25.3l-.8 .8h-150v-10.8l3.1-3.1v-4.8M146.6 58.5v5M23.3 77.8l-2.5 2.5v10.2l-3.4 3.4M38.4 75.4h-1.2l-9.7 9.7v8.8M42.2 75.4h1.2l.7 .7v3.4l-6.4 6.4v8M46.6 64.4l-2.1 .1M48.5 75.4h-.3l-1.6 1.6v15.6l1.3 1.3M52.2 72.9h-16.4l-6.9 7h-3.3M52.2 75.4v.2M52.3 60.7h2.2l2.7 2.7v6.6l3.5 3.5M52.5 65.7h2.1l.7 .6v13.3l2.1 2.2v2.1l1.9 1.9 2-.1v-8l1.7-1.7h.2"/>
<path d="M63.2 73.5h-3.8l-1 1 .9 .9v7.7M63.2 78.6v11.3l4 4h3M65.8 78.6v7.2l4.9 4.9h1.6l.4 .4M65.8 73.5l.3 .3h2.9M69.3 68.7l-2.2 2.3h-1.3M70.1 78.6h-4.3M74.2 73.5l-2.5 2.5h-5.9M74.2 78.5h-8.3l-.1 .1M83.3 75.3h-1.2l-6.8 6.9v11.7M88.4 75.3h-1.2l-.7 .7v1.5l-2.2 2.2v10.7l1.1 1.1v2.4M93.5 75.3h-1.2l-.7 .7v13.9l4 4M98.6 75.3h-1.2l-.7 .7v8.8l9 9.1"/>
<path d="M146.4 63.6h4.9M23.3 83.3v9.8l-.8 .8M32.6 87.1v6.8M42.8 87.1v6.8M42.8 87v.1M52.9 87v6.9M53.5 80.5l1.3 1.4v8.7l3.2 3.3M68.1 81.4l-.4 .4v3.1l2.3 2.2M78.1 87.1l2.2 2.3v4.5M86.2 86.9v2.7l4.3 4.3M94.3 87.1l6.4 6.4v.4M102.4 87.1l6.7 6.8h1.7"/>
</g>
<g fill="#fff" stroke="#fff" stroke-width=".21">
<circle cx="29.5" cy="41.8" r=".2"/>
<circle cx="97.4" cy="57.8" r=".2"/>
<circle cx="97.7" cy="61.3" r=".2"/>
<circle cx="110" cy="61.4" r=".2"/>
<circle cx="111.5" cy="70.1" r=".2"/>
<circle cx="103" cy="69.9" r=".2"/>
<circle cx="96.1" cy="70.1" r=".2"/>
<circle cx="70" cy="81.9" r=".2"/>
<circle cx="72.9" cy="85.7" r=".2"/>
<circle cx="72.9" cy="88.4" r=".2"/>
<circle cx="61.1" cy="88.8" r=".2"/>
<circle cx="57.3" cy="77.8" r=".2"/>
<circle cx="67.7" cy="90.9" r=".2"/>
<circle cx="65.6" cy="88.8" r=".2"/>
<circle cx="61" cy="94.1" r=".2"/>
<circle cx="57.4" cy="89.9" r=".2"/>
<circle cx="79.9" cy="80.5" r=".2"/>
<circle cx="82.3" cy="82.8" r=".2"/>
<circle cx="68.2" cy="60.9" r=".2"/>
<circle cx="67.6" cy="55.6" r=".2"/>
<circle cx="64.6" cy="55.4" r=".2"/>
<circle cx="70.2" cy="47" r=".2"/>
<circle cx="73.7" cy="46.9" r=".2"/>
<circle cx="46.9" cy="41.8" r=".2"/>
<circle cx="35.4" cy="46.9" r=".2"/>
<circle cx="55.2" cy="46.5" r=".2"/>
<circle cx="60.3" cy="50.1" r=".2"/>
<circle cx="64.5" cy="50.1" r=".2"/>
<circle cx="101.1" cy="35.8" r=".2"/>
<circle cx="99.1" cy="35.2" r=".2"/>
<circle cx="105.1" cy="29" r=".2"/>
<circle cx="107.3" cy="29" r=".2"/>
<circle cx="107.3" cy="33.6" r=".2"/>
<circle cx="104.8" cy="34.2" r=".2"/>
<circle cx="104.7" cy="37.3" r=".2"/>
<circle cx="137.9" cy="45.7" r=".2"/>
<circle cx="138.9" cy="52.6" r=".2"/>
<circle cx="142.3" cy="50" r=".2"/>
<circle cx="132.2" cy="40.9" r=".2"/>
<circle cx="132.5" cy="46.5" r=".2"/>
<circle cx="118.2" cy="37.4" r=".2"/>
<circle cx="113.8" cy="32.7" r=".2"/>
<circle cx="113.9" cy="42.5" r=".2"/>
<circle cx="117.5" cy="46.1" r=".2"/>
<circle cx="122.7" cy="41.6" r=".2"/>
<circle cx="130" cy="42.4" r=".2"/>
<circle cx="130" cy="46.7" r=".2"/>
<circle cx="122.6" cy="50.6" r=".2"/>
<circle cx="123.1" cy="85.9" r=".2"/>
<circle cx="123" cy="83.6" r=".2"/>
<circle cx="130.9" cy="86.6" r=".2"/>
<circle cx="127.6" cy="86.6" r=".2"/>
<circle cx="110.8" cy="83.4" r=".2"/>
<circle cx="117.4" cy="89.6" r=".2"/>
<circle cx="126.7" cy="89.4" r=".2"/>
<circle cx="120.4" cy="92.1" r=".2"/>
<circle cx="161.5" cy="90" r=".2"/>
<circle cx="156.3" cy="90" r=".2"/>
<circle cx="161.5" cy="84.1" r=".2"/>
<circle cx="163.8" cy="78.6" r=".2"/>
<circle cx="163.6" cy="73.7" r=".2"/>
<circle cx="139.6" cy="81.5" r=".2"/>
<circle cx="143.5" cy="86.4" r=".2"/>
<circle cx="135" cy="83.6" r=".2"/>
<circle cx="135" cy="86.1" r=".2"/>
<circle cx="135" cy="70.7" r=".2"/>
<circle cx="131" cy="69.2" r=".2"/>
<circle cx="128.6" cy="69.1" r=".2"/>
<circle cx="118" cy="69.6" r=".2"/>
<circle cx="121.8" cy="63.7" r=".2"/>
<circle cx="113.7" cy="53.2" r=".2"/>
<circle cx="112.9" cy="56.5" r=".2"/>
<circle cx="116.5" cy="58" r=".2"/>
<circle cx="116.5" cy="56.4" r=".2"/>
<circle cx="93.1" cy="55.7" r=".2"/>
<circle cx="88.7" cy="55.7" r=".2"/>
<circle cx="84.1" cy="57.1" r=".2"/>
<circle cx="81.2" cy="58.8" r=".2"/>
<circle cx="77.9" cy="76.7" r=".2"/>
<circle cx="81.2" cy="73" r=".2"/>
<circle cx="81.4" cy="79" r=".2"/>
<circle cx="76.3" cy="74.2" r=".2"/>
<circle cx="72.8" cy="72.3" r=".2"/>
<circle cx="71.3" cy="70.5" r=".2"/>
<circle cx="78.3" cy="71" r=".2"/>
<circle cx="75.7" cy="67.4" r=".2"/>
<circle cx="70.6" cy="64.8" r=".2"/>
<circle cx="29.9" cy="86.1" r=".2"/>
<circle cx="30.1" cy="91.2" r=".2"/>
<circle cx="35.1" cy="85.6" r=".2"/>
<circle cx="36.4" cy="79.3" r=".2"/>
<circle cx="39.6" cy="80.9" r=".2"/>
<circle cx="40.3" cy="75.4" r=".2"/>
<circle cx="49" cy="90.6" r=".2"/>
<circle cx="50.8" cy="92" r=".2"/>
<circle cx="50.8" cy="88.4" r=".2"/>
<circle cx="51.4" cy="80.3" r=".2"/>
<circle cx="50.7" cy="83.2" r=".2"/>
<circle cx="48.7" cy="81.3" r=".2"/>
<circle cx="48.6" cy="85.3" r=".2"/>
<circle cx="44.7" cy="88.8" r=".2"/>
<circle cx="44.6" cy="85.3" r=".2"/>
<circle cx="112.7" cy="49.6" r=".2"/>
<circle cx="102" cy="77.8" r=".2"/>
<circle cx="114.7" cy="78.1" r=".2"/>
<circle cx="127.1" cy="78.4" r=".2"/>
<circle cx="159.1" cy="78.6" r=".2"/>
<circle cx="154.1" cy="78.6" r=".2"/>
<circle cx="145.4" cy="78.6" r=".2"/>
<circle cx="140.3" cy="78.6" r=".2"/>
<circle cx="136.8" cy="78.6" r=".2"/>
<circle cx="138.3" cy="41.5" r=".2"/>
<circle cx="137.3" cy="37.9" r=".2"/>
<circle cx="87.5" cy="28.3" r=".2"/>
<circle cx="59.3" cy="83.1" r=".2"/>
<circle cx="61.2" cy="85.8" r=".2"/>
<circle cx="68.1" cy="81.4" r=".2"/>
<circle cx="96.5" cy="47.9" r=".2"/>
<circle cx="90.3" cy="48.7" r=".2"/>
<circle cx="88.5" cy="48.7" r=".2"/>
<circle cx="144.5" cy="28.5" r=".2"/>
<circle cx="74.9" cy="50.4" r=".2"/>
<circle cx="117.1" cy="60.8" r=".2"/>
<circle cx="143.8" cy="67.6" r=".2"/>
<circle cx="25.6" cy="79.9" r=".2"/>
<circle cx="49.2" cy="52" r=".2"/>
<circle cx="55.4" cy="57.3" r=".2"/>
<circle cx="72.6" cy="65.6" r=".2"/>
<circle cx="91.1" cy="68" r=".2"/>
<circle cx="90.1" cy="70.2" r=".2"/>
<circle cx="53.8" cy="62.7" r=".2"/>
<circle cx="75.9" cy="65.8" r=".2"/>
<circle cx="49.4" cy="69.7" r=".2"/>
<circle cx="79.1" cy="65.6" r=".2"/>
<circle cx="46.6" cy="64.4" r=".2"/>
<circle cx="45.9" cy="67.4" r=".2"/>
<circle cx="82.5" cy="65.8" r=".2"/>
<circle cx="86.9" cy="58.1" r=".2"/>
<circle cx="86" cy="48.2" r=".2"/>
<circle cx="114.4" cy="55.5" r=".2"/>
<circle cx="104" cy="51.2" r=".2"/>
<circle cx="119" cy="53.4" r=".2"/>
<circle cx="117.7" cy="55" r=".2"/>
<circle cx="93.6" cy="69.4" r=".2"/>
<circle cx="94.1" cy="68" r=".2"/>
<circle cx="79.8" cy="70.6" r=".2"/>
<circle cx="80" cy="68" r=".2"/>
<circle cx="72.7" cy="91.1" r=".2"/>
<circle cx="100.5" cy="58.5" r=".2"/>
<circle cx="97.9" cy="44.7" r=".2"/>
<circle cx="96" cy="44" r=".2"/>
<circle cx="103" cy="46.6" r=".2"/>
<circle cx="72.2" cy="57.1" r=".2"/>
<circle cx="79.8" cy="49.3" r=".2"/>
<circle cx="79.8" cy="46.1" r=".2"/>
<circle cx="76.4" cy="45.1" r=".2"/>
<circle cx="76.3" cy="40.7" r=".2"/>
<circle cx="63.5" cy="42.4" r=".2"/>
<circle cx="64.7" cy="37.4" r=".2"/>
<circle cx="60.5" cy="68.5" r=".2"/>
<circle cx="62.4" cy="42.5" r=".2"/>
<circle cx="55" cy="39.5" r=".2"/>
<circle cx="22.7" cy="43" r=".2"/>
<circle cx="19.7" cy="39.5" r=".2"/>
<circle cx="63.1" cy="56.6" r=".2"/>
<circle cx="23.8" cy="43" r=".2"/>
<circle cx="23.8" cy="39.8" r=".2"/>
<circle cx="61.1" cy="56.5" r=".2"/>
<circle cx="45.2" cy="49.5" r=".2"/>
<circle cx="44" cy="37.3" r=".2"/>
<circle cx="70" cy="60.4" r=".2"/>
<circle cx="70.2" cy="57.1" r=".2"/>
<circle cx="104" cy="56.2" r=".2"/>
<circle cx="107.1" cy="44.6" r=".2"/>
<circle cx="108.1" cy="43.5" r=".2"/>
<circle cx="107.1" cy="41.5" r=".2"/>
<circle cx="101" cy="41" r=".2"/>
<circle cx="81.7" cy="43.3" r=".2"/>
<circle cx="86.6" cy="44" r=".2"/>
<circle cx="71.2" cy="57.1" r=".2"/>
<circle cx="78" cy="50.1" r=".2"/>
<circle cx="79.9" cy="42.1" r=".2"/>
<circle cx="74.1" cy="40.5" r=".2"/>
<circle cx="75.6" cy="44.5" r=".2"/>
<circle cx="58.1" cy="41.5" r=".2"/>
<circle cx="61.4" cy="39.1" r=".2"/>
<circle cx="54.7" cy="43.1" r=".2"/>
<circle cx="51.2" cy="39.7" r=".2"/>
<circle cx="43.3" cy="42.8" r=".2"/>
<circle cx="43.3" cy="38.5" r=".2"/>
<circle cx="62.1" cy="56.6" r=".2"/>
<circle cx="34.7" cy="49" r=".2"/>
<circle cx="33.2" cy="40.2" r=".2"/>
<circle cx="30.1" cy="39.5" r=".2"/>
<circle cx="31.4" cy="43.4" r=".2"/>
<circle cx="122.6" cy="36.9" r=".2"/>
<circle cx="121.8" cy="39.5" r=".2"/>
<circle cx="121.8" cy="54.7" r=".2"/>
<circle cx="121.5" cy="57.4" r=".2"/>
<circle cx="105.5" cy="42" r=".2"/>
<circle cx="103.5" cy="39.3" r=".2"/>
<circle cx="126.4" cy="57.8" r=".2"/>
<circle cx="124.1" cy="55.5" r=".2"/>
<circle cx="115.2" cy="61.3" r=".2"/>
<circle cx="123.3" cy="62.3" r=".2"/>
<circle cx="128.9" cy="66.1" r=".2"/>
<circle cx="130.9" cy="66.1" r=".2"/>
<circle cx="137.6" cy="67.9" r=".2"/>
<circle cx="140.1" cy="67.9" r=".2"/>
<circle cx="105.3" cy="52.7" r=".2"/>
<circle cx="105" cy="59.4" r=".2"/>
<circle cx="103.3" cy="44.8" r=".2"/>
<circle cx="102.8" cy="40" r=".2"/>
<circle cx="122.8" cy="61.5" r=".2"/>
<circle cx="128.9" cy="67.4" r=".2"/>
<circle cx="130.9" cy="67.4" r=".2"/>
<circle cx="137.6" cy="69.4" r=".2"/>
<circle cx="139.3" cy="69.4" r=".2"/>
<circle cx="120.3" cy="50.4" r=".2"/>
<circle cx="125.8" cy="58.6" r=".2"/>
<circle cx="116.2" cy="69.7" r=".2"/>
<circle cx="119.3" cy="52.4" r=".2"/>
<circle cx="106.3" cy="70.2" r=".2"/>
<circle cx="111.4" cy="64.5" r=".2"/>
<circle cx="111.4" cy="59.8" r=".2"/>
<circle cx="111.5" cy="57" r=".2"/>
<circle cx="115.1" cy="46.6" r=".2"/>
<circle cx="119.5" cy="54.9" r=".2"/>
<circle cx="121" cy="53.4" r=".2"/>
<circle cx="120.2" cy="55.6" r=".2"/>
<circle cx="96.5" cy="49.3" r=".2"/>
<circle cx="95.4" cy="49.3" r=".2"/>
<circle cx="53.5" cy="80.5" r=".2"/>
<circle cx="113.2" cy="139.3" r=".4"/>
<circle cx="113.2" cy="117.3" r=".4"/>
<circle cx="115.7" cy="139.3" r=".4"/>
<circle cx="115.7" cy="117.3" r=".4"/>
<circle cx="118.3" cy="139.3" r=".4"/>
<circle cx="118.3" cy="117.3" r=".4"/>
<circle cx="120.8" cy="139.3" r=".4"/>
<circle cx="120.8" cy="117.3" r=".4"/>
<circle cx="123.4" cy="139.3" r=".4"/>
<circle cx="123.4" cy="117.3" r=".4"/>
<circle cx="125.9" cy="139.3" r=".4"/>
<circle cx="125.9" cy="117.3" r=".4"/>
<circle cx="128.4" cy="139.3" r=".4"/>
<circle cx="128.4" cy="117.3" r=".4"/>
<circle cx="131" cy="139.3" r=".4"/>
<circle cx="131" cy="117.3" r=".4"/>
<circle cx="133.5" cy="139.3" r=".4"/>
<circle cx="133.5" cy="117.3" r=".4"/>
<circle cx="136.1" cy="139.3" r=".4"/>
<circle cx="136.1" cy="117.3" r=".4"/>
<circle cx="138.6" cy="139.3" r=".4"/>
<circle cx="138.6" cy="117.3" r=".4"/>
<circle cx="141.1" cy="139.3" r=".4"/>
<circle cx="141.1" cy="117.3" r=".4"/>
<circle cx="143.7" cy="139.3" r=".4"/>
<circle cx="143.7" cy="117.3" r=".4"/>
<circle cx="146.2" cy="139.3" r=".4"/>
<circle cx="146.2" cy="117.3" r=".4"/>
<circle cx="148.8" cy="139.3" r=".4"/>
<circle cx="148.8" cy="117.3" r=".4"/>
<circle cx="151.3" cy="139.3" r=".4"/>
<circle cx="151.3" cy="117.3" r=".4"/>
<circle cx="153.8" cy="139.3" r=".4"/>
<circle cx="153.8" cy="117.3" r=".4"/>
<circle cx="156.4" cy="139.3" r=".4"/>
<circle cx="156.4" cy="117.3" r=".4"/>
<circle cx="158.9" cy="139.3" r=".4"/>
<circle cx="158.9" cy="117.3" r=".4"/>
<circle cx="161.5" cy="139.3" r=".4"/>
<circle cx="161.5" cy="117.3" r=".4"/>
<circle cx="163.6" cy="93.9" r=".45"/>
<circle cx="158.5" cy="93.9" r=".45"/>
<circle cx="153.5" cy="93.9" r=".45"/>
<circle cx="148.4" cy="93.9" r=".45"/>
<circle cx="143.3" cy="93.9" r=".45"/>
<circle cx="138.2" cy="93.9" r=".45"/>
<circle cx="133.1" cy="93.9" r=".45"/>
<circle cx="128.1" cy="93.9" r=".45"/>
<circle cx="123" cy="93.9" r=".45"/>
<circle cx="98.6" cy="77.8" r=".5"/>
<circle cx="98.6" cy="75.3" r=".5"/>
<circle cx="98.6" cy="72.8" r=".5"/>
<circle cx="164.4" cy="162.6" r=".5"/>
<circle cx="161.9" cy="162.6" r=".5"/>
<circle cx="159.4" cy="162.6" r=".5"/>
<circle cx="164" cy="52.2" r=".5"/>
<circle cx="164" cy="49.6" r=".5"/>
<circle cx="28.6" cy="53.9" r=".5"/>
<circle cx="26" cy="53.9" r=".5"/>
<circle cx="151.4" cy="111.8" r=".5"/>
<circle cx="151.4" cy="109.2" r=".5"/>
<circle cx="48.5" cy="72.9" r=".5"/>
<circle cx="48.5" cy="75.4" r=".5"/>
<circle cx="48.5" cy="78" r=".5"/>
<circle cx="52.2" cy="78" r=".5"/>
<circle cx="52.2" cy="75.4" r=".5"/>
<circle cx="52.2" cy="72.9" r=".5"/>
<circle cx="42.2" cy="72.9" r=".5"/>
<circle cx="42.2" cy="75.4" r=".5"/>
<circle cx="42.2" cy="78" r=".5"/>
<circle cx="83.3" cy="72.8" r=".5"/>
<circle cx="83.3" cy="75.3" r=".5"/>
<circle cx="83.3" cy="77.8" r=".5"/>
<circle cx="88.4" cy="77.8" r=".5"/>
<circle cx="88.4" cy="75.3" r=".5"/>
<circle cx="88.4" cy="72.8" r=".5"/>
<circle cx="93.5" cy="72.8" r=".5"/>
<circle cx="93.5" cy="75.3" r=".5"/>
<circle cx="93.5" cy="77.8" r=".5"/>
<circle cx="38.4" cy="72.9" r=".5"/>
<circle cx="38.4" cy="75.4" r=".5"/>
<circle cx="38.4" cy="78" r=".5"/>
<circle cx="139.9" cy="162.6" r=".5"/>
<circle cx="142.4" cy="162.6" r=".5"/>
<circle cx="145" cy="162.6" r=".5"/>
<circle cx="147.5" cy="162.6" r=".5"/>
<circle cx="150" cy="162.6" r=".5"/>
<circle cx="152.6" cy="162.6" r=".5"/>
<circle cx="118.2" cy="104.5" r=".5"/>
<circle cx="118.2" cy="107" r=".5"/>
<circle cx="120.8" cy="104.5" r=".5"/>
<circle cx="120.8" cy="107" r=".5"/>
<circle cx="123.3" cy="104.5" r=".5"/>
<circle cx="123.3" cy="107" r=".5"/>
<circle cx="125.8" cy="104.5" r=".5"/>
<circle cx="125.8" cy="107" r=".5"/>
<circle cx="128.4" cy="104.5" r=".5"/>
<circle cx="128.4" cy="107" r=".5"/>
<circle cx="63.2" cy="60.8" r=".5"/>
<circle cx="65.8" cy="60.8" r=".5"/>
<circle cx="63.2" cy="63.3" r=".5"/>
<circle cx="65.8" cy="63.3" r=".5"/>
<circle cx="63.2" cy="65.9" r=".5"/>
<circle cx="65.8" cy="65.9" r=".5"/>
<circle cx="63.2" cy="68.4" r=".5"/>
<circle cx="65.8" cy="68.4" r=".5"/>
<circle cx="63.2" cy="71" r=".5"/>
<circle cx="65.8" cy="71" r=".5"/>
<circle cx="63.2" cy="73.5" r=".5"/>
<circle cx="65.8" cy="73.5" r=".5"/>
<circle cx="63.2" cy="76" r=".5"/>
<circle cx="65.8" cy="76" r=".5"/>
<circle cx="63.2" cy="78.6" r=".5"/>
<circle cx="65.8" cy="78.6" r=".5"/>
<circle cx="85.2" cy="107.2" r=".5"/>
<circle cx="85.2" cy="109.8" r=".5"/>
<circle cx="87.8" cy="107.2" r=".5"/>
<circle cx="87.8" cy="109.8" r=".5"/>
<circle cx="90.3" cy="107.2" r=".5"/>
<circle cx="90.3" cy="109.8" r=".5"/>
<circle cx="92.8" cy="107.2" r=".5"/>
<circle cx="92.8" cy="109.8" r=".5"/>
<circle cx="95.4" cy="107.2" r=".5"/>
<circle cx="95.4" cy="109.8" r=".5"/>
<circle cx="97.9" cy="107.2" r=".5"/>
<circle cx="97.9" cy="109.8" r=".5"/>
<circle cx="100.5" cy="107.2" r=".5"/>
<circle cx="100.5" cy="109.8" r=".5"/>
<circle cx="103" cy="107.2" r=".5"/>
<circle cx="103" cy="109.8" r=".5"/>
<circle cx="103" cy="30.3" r=".5"/>
<circle cx="103" cy="32.9" r=".5"/>
<circle cx="100.5" cy="30.3" r=".5"/>
<circle cx="100.5" cy="32.9" r=".5"/>
<circle cx="97.9" cy="30.3" r=".5"/>
<circle cx="97.9" cy="32.9" r=".5"/>
<circle cx="95.4" cy="30.3" r=".5"/>
<circle cx="95.4" cy="32.9" r=".5"/>
<circle cx="92.8" cy="30.3" r=".5"/>
<circle cx="92.8" cy="32.9" r=".5"/>
<circle cx="90.3" cy="30.3" r=".5"/>
<circle cx="90.3" cy="32.9" r=".5"/>
<circle cx="87.8" cy="30.3" r=".5"/>
<circle cx="87.8" cy="32.9" r=".5"/>
<circle cx="85.2" cy="30.3" r=".5"/>
<circle cx="85.2" cy="32.9" r=".5"/>
<circle cx="17.4" cy="93.9" r=".45"/>
<circle cx="22.5" cy="93.9" r=".45"/>
<circle cx="27.5" cy="93.9" r=".45"/>
<circle cx="32.6" cy="93.9" r=".45"/>
<circle cx="37.7" cy="93.9" r=".45"/>
<circle cx="42.8" cy="93.9" r=".45"/>
<circle cx="47.9" cy="93.9" r=".45"/>
<circle cx="52.9" cy="93.9" r=".45"/>
<circle cx="58" cy="93.9" r=".45"/>
<circle cx="123" cy="18.3" r=".45"/>
<circle cx="128" cy="18.3" r=".45"/>
<circle cx="133.1" cy="18.3" r=".45"/>
<circle cx="138.2" cy="18.3" r=".45"/>
<circle cx="143.3" cy="18.3" r=".45"/>
<circle cx="148.4" cy="18.3" r=".45"/>
<circle cx="153.4" cy="18.3" r=".45"/>
<circle cx="158.5" cy="18.3" r=".45"/>
<circle cx="163.6" cy="18.3" r=".45"/>
<circle cx="110.8" cy="18.3" r=".45"/>
<circle cx="105.7" cy="18.3" r=".45"/>
<circle cx="100.6" cy="18.3" r=".45"/>
<circle cx="95.6" cy="18.3" r=".45"/>
<circle cx="90.5" cy="18.3" r=".45"/>
<circle cx="85.4" cy="18.3" r=".45"/>
<circle cx="80.3" cy="18.3" r=".45"/>
<circle cx="75.2" cy="18.3" r=".45"/>
<circle cx="70.2" cy="18.3" r=".45"/>
<circle cx="70.2" cy="93.9" r=".45"/>
<circle cx="75.3" cy="93.9" r=".45"/>
<circle cx="80.3" cy="93.9" r=".45"/>
<circle cx="85.4" cy="93.9" r=".45"/>
<circle cx="90.5" cy="93.9" r=".45"/>
<circle cx="95.6" cy="93.9" r=".45"/>
<circle cx="100.7" cy="93.9" r=".45"/>
<circle cx="105.7" cy="93.9" r=".45"/>
<circle cx="110.8" cy="93.9" r=".45"/>
<circle cx="17.4" cy="18.3" r=".45"/>
<circle cx="22.4" cy="18.3" r=".45"/>
<circle cx="27.5" cy="18.3" r=".45"/>
<circle cx="32.6" cy="18.3" r=".45"/>
<circle cx="37.7" cy="18.3" r=".45"/>
<circle cx="42.8" cy="18.3" r=".45"/>
<circle cx="47.8" cy="18.3" r=".45"/>
<circle cx="52.9" cy="18.3" r=".45"/>
<circle cx="58" cy="18.3" r=".45"/>
<circle cx="18.2" cy="83.3" r=".5"/>
<circle cx="20.8" cy="83.3" r=".5"/>
<circle cx="23.3" cy="83.3" r=".5"/>
<circle cx="145.7" cy="50.2" r=".4"/>
<circle cx="145.7" cy="52.7" r=".4"/>
<circle cx="31.7" cy="72.2" r=".4"/>
<circle cx="29.2" cy="72.2" r=".4"/>
</g>
</svg>
